VERSION 5.7 ;
  NOWIREEXTENSIONATPIN ON ;
  DIVIDERCHAR "/" ;
  BUSBITCHARS "[]" ;
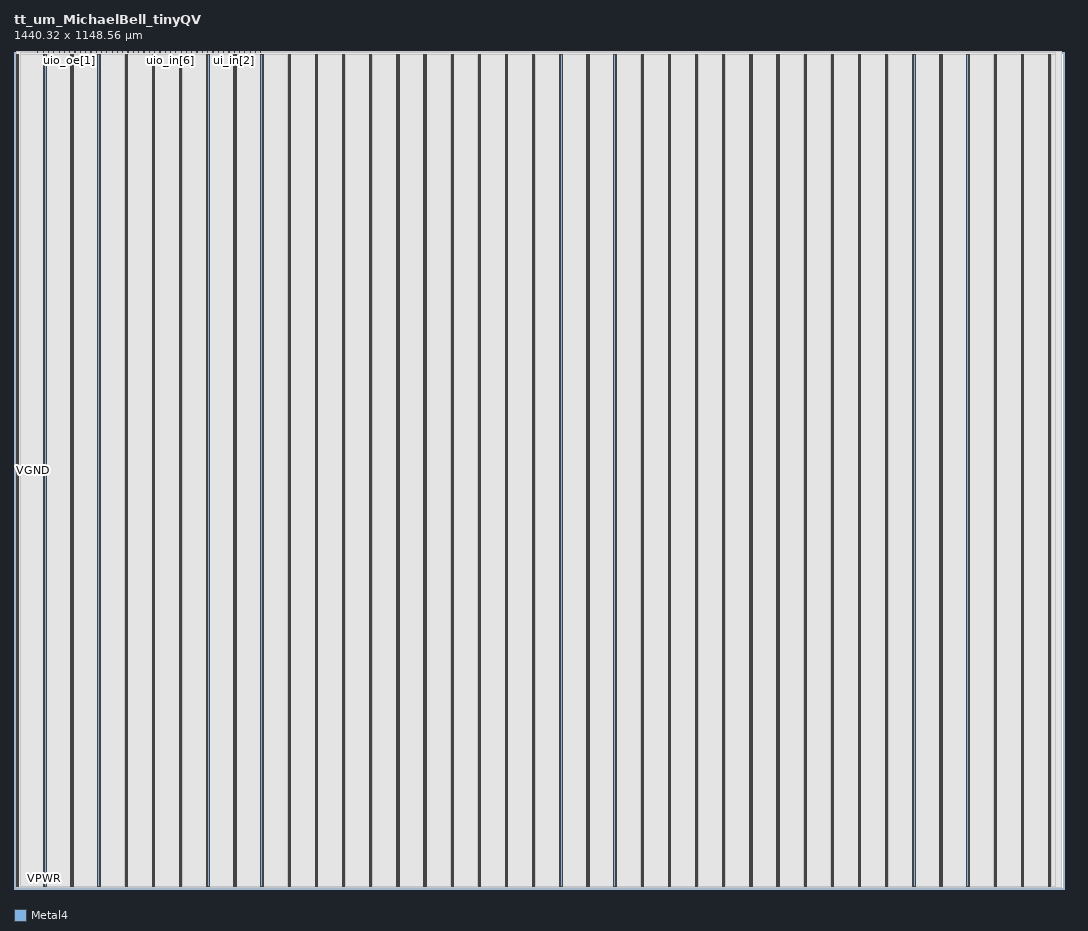
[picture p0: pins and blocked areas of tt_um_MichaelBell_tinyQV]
MACRO tt_um_MichaelBell_tinyQV
  CLASS BLOCK ;
  FOREIGN tt_um_MichaelBell_tinyQV ;
  ORIGIN 0.000 0.000 ;
  SIZE 1440.320 BY 1148.560 ;
  PIN VGND
    DIRECTION INOUT ;
    USE GROUND ;
    PORT
      LAYER Metal4 ;
        RECT 5.250 3.620 6.750 1144.940 ;
    END
    PORT
      LAYER Metal4 ;
        RECT 42.500 3.620 44.000 1144.940 ;
    END
    PORT
      LAYER Metal4 ;
        RECT 79.750 3.620 81.250 1144.940 ;
    END
    PORT
      LAYER Metal4 ;
        RECT 117.000 3.620 118.500 1144.940 ;
    END
    PORT
      LAYER Metal4 ;
        RECT 154.250 3.620 155.750 1144.940 ;
    END
    PORT
      LAYER Metal4 ;
        RECT 191.500 3.620 193.000 1144.940 ;
    END
    PORT
      LAYER Metal4 ;
        RECT 228.750 3.620 230.250 1144.940 ;
    END
    PORT
      LAYER Metal4 ;
        RECT 266.000 3.620 267.500 1144.940 ;
    END
    PORT
      LAYER Metal4 ;
        RECT 303.250 3.620 304.750 1144.940 ;
    END
    PORT
      LAYER Metal4 ;
        RECT 340.500 3.620 342.000 1144.940 ;
    END
    PORT
      LAYER Metal4 ;
        RECT 377.750 3.620 379.250 1144.940 ;
    END
    PORT
      LAYER Metal4 ;
        RECT 415.000 3.620 416.500 1144.940 ;
    END
    PORT
      LAYER Metal4 ;
        RECT 452.250 3.620 453.750 1144.940 ;
    END
    PORT
      LAYER Metal4 ;
        RECT 489.500 3.620 491.000 1144.940 ;
    END
    PORT
      LAYER Metal4 ;
        RECT 526.750 3.620 528.250 1144.940 ;
    END
    PORT
      LAYER Metal4 ;
        RECT 564.000 3.620 565.500 1144.940 ;
    END
    PORT
      LAYER Metal4 ;
        RECT 601.250 3.620 602.750 1144.940 ;
    END
    PORT
      LAYER Metal4 ;
        RECT 638.500 3.620 640.000 1144.940 ;
    END
    PORT
      LAYER Metal4 ;
        RECT 675.750 3.620 677.250 1144.940 ;
    END
    PORT
      LAYER Metal4 ;
        RECT 713.000 3.620 714.500 1144.940 ;
    END
    PORT
      LAYER Metal4 ;
        RECT 750.250 3.620 751.750 1144.940 ;
    END
    PORT
      LAYER Metal4 ;
        RECT 787.500 3.620 789.000 1144.940 ;
    END
    PORT
      LAYER Metal4 ;
        RECT 824.750 3.620 826.250 1144.940 ;
    END
    PORT
      LAYER Metal4 ;
        RECT 862.000 3.920 863.500 1144.640 ;
    END
    PORT
      LAYER Metal4 ;
        RECT 899.250 3.920 900.750 1144.640 ;
    END
    PORT
      LAYER Metal4 ;
        RECT 936.500 3.920 938.000 1144.640 ;
    END
    PORT
      LAYER Metal4 ;
        RECT 973.750 3.920 975.250 1144.640 ;
    END
    PORT
      LAYER Metal4 ;
        RECT 1011.000 3.920 1012.500 1144.640 ;
    END
    PORT
      LAYER Metal4 ;
        RECT 1048.250 3.920 1049.750 1144.640 ;
    END
    PORT
      LAYER Metal4 ;
        RECT 1085.500 3.920 1087.000 1144.640 ;
    END
    PORT
      LAYER Metal4 ;
        RECT 1122.750 3.920 1124.250 1144.640 ;
    END
    PORT
      LAYER Metal4 ;
        RECT 1160.000 3.920 1161.500 1144.640 ;
    END
    PORT
      LAYER Metal4 ;
        RECT 1197.250 3.920 1198.750 1144.640 ;
    END
    PORT
      LAYER Metal4 ;
        RECT 1234.500 3.920 1236.000 1144.640 ;
    END
    PORT
      LAYER Metal4 ;
        RECT 1271.750 3.920 1273.250 1144.640 ;
    END
    PORT
      LAYER Metal4 ;
        RECT 1309.000 3.920 1310.500 1144.640 ;
    END
    PORT
      LAYER Metal4 ;
        RECT 1346.250 3.920 1347.750 1144.640 ;
    END
    PORT
      LAYER Metal4 ;
        RECT 1383.500 3.920 1385.000 1144.640 ;
    END
    PORT
      LAYER Metal4 ;
        RECT 1420.750 3.920 1422.250 1144.640 ;
    END
  END VGND
  PIN VPWR
    DIRECTION INOUT ;
    USE POWER ;
    PORT
      LAYER Metal4 ;
        RECT 3.470 3.620 4.970 1144.940 ;
    END
    PORT
      LAYER Metal4 ;
        RECT 40.720 3.620 42.220 1144.940 ;
    END
    PORT
      LAYER Metal4 ;
        RECT 77.970 3.620 79.470 1144.940 ;
    END
    PORT
      LAYER Metal4 ;
        RECT 115.220 3.620 116.720 1144.940 ;
    END
    PORT
      LAYER Metal4 ;
        RECT 152.470 3.620 153.970 1144.940 ;
    END
    PORT
      LAYER Metal4 ;
        RECT 189.720 3.620 191.220 1144.940 ;
    END
    PORT
      LAYER Metal4 ;
        RECT 226.970 3.620 228.470 1144.940 ;
    END
    PORT
      LAYER Metal4 ;
        RECT 264.220 3.620 265.720 1144.940 ;
    END
    PORT
      LAYER Metal4 ;
        RECT 301.470 3.620 302.970 1144.940 ;
    END
    PORT
      LAYER Metal4 ;
        RECT 338.720 3.620 340.220 1144.940 ;
    END
    PORT
      LAYER Metal4 ;
        RECT 375.970 3.620 377.470 1144.940 ;
    END
    PORT
      LAYER Metal4 ;
        RECT 413.220 3.620 414.720 1144.940 ;
    END
    PORT
      LAYER Metal4 ;
        RECT 450.470 3.620 451.970 1144.940 ;
    END
    PORT
      LAYER Metal4 ;
        RECT 487.720 3.620 489.220 1144.940 ;
    END
    PORT
      LAYER Metal4 ;
        RECT 524.970 3.620 526.470 1144.940 ;
    END
    PORT
      LAYER Metal4 ;
        RECT 562.220 3.620 563.720 1144.940 ;
    END
    PORT
      LAYER Metal4 ;
        RECT 599.470 3.620 600.970 1144.940 ;
    END
    PORT
      LAYER Metal4 ;
        RECT 636.720 3.620 638.220 1144.940 ;
    END
    PORT
      LAYER Metal4 ;
        RECT 673.970 3.620 675.470 1144.940 ;
    END
    PORT
      LAYER Metal4 ;
        RECT 711.220 3.620 712.720 1144.940 ;
    END
    PORT
      LAYER Metal4 ;
        RECT 748.470 3.620 749.970 1144.940 ;
    END
    PORT
      LAYER Metal4 ;
        RECT 785.720 3.620 787.220 1144.940 ;
    END
    PORT
      LAYER Metal4 ;
        RECT 822.970 3.620 824.470 1144.940 ;
    END
    PORT
      LAYER Metal4 ;
        RECT 860.220 3.920 861.720 1144.640 ;
    END
    PORT
      LAYER Metal4 ;
        RECT 897.470 3.920 898.970 1144.640 ;
    END
    PORT
      LAYER Metal4 ;
        RECT 934.720 3.920 936.220 1144.640 ;
    END
    PORT
      LAYER Metal4 ;
        RECT 971.970 3.920 973.470 1144.640 ;
    END
    PORT
      LAYER Metal4 ;
        RECT 1009.220 3.920 1010.720 1144.640 ;
    END
    PORT
      LAYER Metal4 ;
        RECT 1046.470 3.920 1047.970 1144.640 ;
    END
    PORT
      LAYER Metal4 ;
        RECT 1083.720 3.920 1085.220 1144.640 ;
    END
    PORT
      LAYER Metal4 ;
        RECT 1120.970 3.920 1122.470 1144.640 ;
    END
    PORT
      LAYER Metal4 ;
        RECT 1158.220 3.920 1159.720 1144.640 ;
    END
    PORT
      LAYER Metal4 ;
        RECT 1195.470 3.920 1196.970 1144.640 ;
    END
    PORT
      LAYER Metal4 ;
        RECT 1232.720 3.920 1234.220 1144.640 ;
    END
    PORT
      LAYER Metal4 ;
        RECT 1269.970 3.920 1271.470 1144.640 ;
    END
    PORT
      LAYER Metal4 ;
        RECT 1307.220 3.920 1308.720 1144.640 ;
    END
    PORT
      LAYER Metal4 ;
        RECT 1344.470 3.920 1345.970 1144.640 ;
    END
    PORT
      LAYER Metal4 ;
        RECT 1381.720 3.920 1383.220 1144.640 ;
    END
    PORT
      LAYER Metal4 ;
        RECT 1418.970 3.920 1420.470 1144.640 ;
    END
  END VPWR
  PIN clk
    DIRECTION INPUT ;
    USE SIGNAL ;
    ANTENNAGATEAREA 9.476000 ;
    PORT
      LAYER Metal4 ;
        RECT 331.090 1147.560 331.390 1148.560 ;
    END
  END clk
  PIN ena
    DIRECTION INPUT ;
    USE SIGNAL ;
    PORT
      LAYER Metal4 ;
        RECT 338.370 1147.560 338.670 1148.560 ;
    END
  END ena
  PIN rst_n
    DIRECTION INPUT ;
    USE SIGNAL ;
    ANTENNAGATEAREA 1.102000 ;
    PORT
      LAYER Metal4 ;
        RECT 323.810 1147.560 324.110 1148.560 ;
    END
  END rst_n
  PIN ui_in[0]
    DIRECTION INPUT ;
    USE SIGNAL ;
    ANTENNAGATEAREA 0.396000 ;
    PORT
      LAYER Metal4 ;
        RECT 316.530 1147.560 316.830 1148.560 ;
    END
  END ui_in[0]
  PIN ui_in[1]
    DIRECTION INPUT ;
    USE SIGNAL ;
    ANTENNAGATEAREA 1.102000 ;
    PORT
      LAYER Metal4 ;
        RECT 309.250 1147.560 309.550 1148.560 ;
    END
  END ui_in[1]
  PIN ui_in[2]
    DIRECTION INPUT ;
    USE SIGNAL ;
    ANTENNAGATEAREA 0.396000 ;
    PORT
      LAYER Metal4 ;
        RECT 301.970 1147.560 302.270 1148.560 ;
    END
  END ui_in[2]
  PIN ui_in[3]
    DIRECTION INPUT ;
    USE SIGNAL ;
    ANTENNAGATEAREA 0.396000 ;
    PORT
      LAYER Metal4 ;
        RECT 294.690 1147.560 294.990 1148.560 ;
    END
  END ui_in[3]
  PIN ui_in[4]
    DIRECTION INPUT ;
    USE SIGNAL ;
    ANTENNAGATEAREA 0.396000 ;
    PORT
      LAYER Metal4 ;
        RECT 287.410 1147.560 287.710 1148.560 ;
    END
  END ui_in[4]
  PIN ui_in[5]
    DIRECTION INPUT ;
    USE SIGNAL ;
    ANTENNAGATEAREA 0.396000 ;
    PORT
      LAYER Metal4 ;
        RECT 280.130 1147.560 280.430 1148.560 ;
    END
  END ui_in[5]
  PIN ui_in[6]
    DIRECTION INPUT ;
    USE SIGNAL ;
    ANTENNAGATEAREA 0.396000 ;
    PORT
      LAYER Metal4 ;
        RECT 272.850 1147.560 273.150 1148.560 ;
    END
  END ui_in[6]
  PIN ui_in[7]
    DIRECTION INPUT ;
    USE SIGNAL ;
    ANTENNAGATEAREA 0.396000 ;
    PORT
      LAYER Metal4 ;
        RECT 265.570 1147.560 265.870 1148.560 ;
    END
  END ui_in[7]
  PIN uio_in[0]
    DIRECTION INPUT ;
    USE SIGNAL ;
    PORT
      LAYER Metal4 ;
        RECT 258.290 1147.560 258.590 1148.560 ;
    END
  END uio_in[0]
  PIN uio_in[1]
    DIRECTION INPUT ;
    USE SIGNAL ;
    ANTENNAGATEAREA 1.102000 ;
    PORT
      LAYER Metal4 ;
        RECT 251.010 1147.560 251.310 1148.560 ;
    END
  END uio_in[1]
  PIN uio_in[2]
    DIRECTION INPUT ;
    USE SIGNAL ;
    ANTENNAGATEAREA 1.102000 ;
    PORT
      LAYER Metal4 ;
        RECT 243.730 1147.560 244.030 1148.560 ;
    END
  END uio_in[2]
  PIN uio_in[3]
    DIRECTION INPUT ;
    USE SIGNAL ;
    PORT
      LAYER Metal4 ;
        RECT 236.450 1147.560 236.750 1148.560 ;
    END
  END uio_in[3]
  PIN uio_in[4]
    DIRECTION INPUT ;
    USE SIGNAL ;
    ANTENNAGATEAREA 1.102000 ;
    PORT
      LAYER Metal4 ;
        RECT 229.170 1147.560 229.470 1148.560 ;
    END
  END uio_in[4]
  PIN uio_in[5]
    DIRECTION INPUT ;
    USE SIGNAL ;
    ANTENNAGATEAREA 1.102000 ;
    PORT
      LAYER Metal4 ;
        RECT 221.890 1147.560 222.190 1148.560 ;
    END
  END uio_in[5]
  PIN uio_in[6]
    DIRECTION INPUT ;
    USE SIGNAL ;
    PORT
      LAYER Metal4 ;
        RECT 214.610 1147.560 214.910 1148.560 ;
    END
  END uio_in[6]
  PIN uio_in[7]
    DIRECTION INPUT ;
    USE SIGNAL ;
    PORT
      LAYER Metal4 ;
        RECT 207.330 1147.560 207.630 1148.560 ;
    END
  END uio_in[7]
  PIN uio_oe[0]
    DIRECTION OUTPUT ;
    USE SIGNAL ;
    ANTENNADIFFAREA 1.182800 ;
    PORT
      LAYER Metal4 ;
        RECT 83.570 1147.560 83.870 1148.560 ;
    END
  END uio_oe[0]
  PIN uio_oe[1]
    DIRECTION OUTPUT ;
    USE SIGNAL ;
    ANTENNADIFFAREA 4.731200 ;
    PORT
      LAYER Metal4 ;
        RECT 76.290 1147.560 76.590 1148.560 ;
    END
  END uio_oe[1]
  PIN uio_oe[2]
    DIRECTION OUTPUT ;
    USE SIGNAL ;
    ANTENNAGATEAREA 0.741000 ;
    ANTENNADIFFAREA 4.731200 ;
    PORT
      LAYER Metal4 ;
        RECT 69.010 1147.560 69.310 1148.560 ;
    END
  END uio_oe[2]
  PIN uio_oe[3]
    DIRECTION OUTPUT ;
    USE SIGNAL ;
    ANTENNADIFFAREA 1.182800 ;
    PORT
      LAYER Metal4 ;
        RECT 61.730 1147.560 62.030 1148.560 ;
    END
  END uio_oe[3]
  PIN uio_oe[4]
    DIRECTION OUTPUT ;
    USE SIGNAL ;
    ANTENNADIFFAREA 1.182800 ;
    PORT
      LAYER Metal4 ;
        RECT 54.450 1147.560 54.750 1148.560 ;
    END
  END uio_oe[4]
  PIN uio_oe[5]
    DIRECTION OUTPUT ;
    USE SIGNAL ;
    ANTENNADIFFAREA 1.182800 ;
    PORT
      LAYER Metal4 ;
        RECT 47.170 1147.560 47.470 1148.560 ;
    END
  END uio_oe[5]
  PIN uio_oe[6]
    DIRECTION OUTPUT ;
    USE SIGNAL ;
    ANTENNADIFFAREA 1.182800 ;
    PORT
      LAYER Metal4 ;
        RECT 39.890 1147.560 40.190 1148.560 ;
    END
  END uio_oe[6]
  PIN uio_oe[7]
    DIRECTION OUTPUT ;
    USE SIGNAL ;
    ANTENNADIFFAREA 1.182800 ;
    PORT
      LAYER Metal4 ;
        RECT 32.610 1147.560 32.910 1148.560 ;
    END
  END uio_oe[7]
  PIN uio_out[0]
    DIRECTION OUTPUT ;
    USE SIGNAL ;
    ANTENNADIFFAREA 1.182800 ;
    PORT
      LAYER Metal4 ;
        RECT 141.810 1147.560 142.110 1148.560 ;
    END
  END uio_out[0]
  PIN uio_out[1]
    DIRECTION OUTPUT ;
    USE SIGNAL ;
    ANTENNADIFFAREA 4.024000 ;
    PORT
      LAYER Metal4 ;
        RECT 134.530 1147.560 134.830 1148.560 ;
    END
  END uio_out[1]
  PIN uio_out[2]
    DIRECTION OUTPUT ;
    USE SIGNAL ;
    ANTENNADIFFAREA 2.609600 ;
    PORT
      LAYER Metal4 ;
        RECT 127.250 1147.560 127.550 1148.560 ;
    END
  END uio_out[2]
  PIN uio_out[3]
    DIRECTION OUTPUT ;
    USE SIGNAL ;
    ANTENNADIFFAREA 7.096800 ;
    PORT
      LAYER Metal4 ;
        RECT 119.970 1147.560 120.270 1148.560 ;
    END
  END uio_out[3]
  PIN uio_out[4]
    DIRECTION OUTPUT ;
    USE SIGNAL ;
    ANTENNADIFFAREA 2.609600 ;
    PORT
      LAYER Metal4 ;
        RECT 112.690 1147.560 112.990 1148.560 ;
    END
  END uio_out[4]
  PIN uio_out[5]
    DIRECTION OUTPUT ;
    USE SIGNAL ;
    ANTENNADIFFAREA 4.731200 ;
    PORT
      LAYER Metal4 ;
        RECT 105.410 1147.560 105.710 1148.560 ;
    END
  END uio_out[5]
  PIN uio_out[6]
    DIRECTION OUTPUT ;
    USE SIGNAL ;
    ANTENNADIFFAREA 4.731200 ;
    PORT
      LAYER Metal4 ;
        RECT 98.130 1147.560 98.430 1148.560 ;
    END
  END uio_out[6]
  PIN uio_out[7]
    DIRECTION OUTPUT ;
    USE SIGNAL ;
    ANTENNADIFFAREA 1.182800 ;
    PORT
      LAYER Metal4 ;
        RECT 90.850 1147.560 91.150 1148.560 ;
    END
  END uio_out[7]
  PIN uo_out[0]
    DIRECTION OUTPUT ;
    USE SIGNAL ;
    ANTENNADIFFAREA 2.365600 ;
    PORT
      LAYER Metal4 ;
        RECT 200.050 1147.560 200.350 1148.560 ;
    END
  END uo_out[0]
  PIN uo_out[1]
    DIRECTION OUTPUT ;
    USE SIGNAL ;
    ANTENNADIFFAREA 2.365600 ;
    PORT
      LAYER Metal4 ;
        RECT 192.770 1147.560 193.070 1148.560 ;
    END
  END uo_out[1]
  PIN uo_out[2]
    DIRECTION OUTPUT ;
    USE SIGNAL ;
    ANTENNADIFFAREA 1.182800 ;
    PORT
      LAYER Metal4 ;
        RECT 185.490 1147.560 185.790 1148.560 ;
    END
  END uo_out[2]
  PIN uo_out[3]
    DIRECTION OUTPUT ;
    USE SIGNAL ;
    ANTENNADIFFAREA 3.879200 ;
    PORT
      LAYER Metal4 ;
        RECT 178.210 1147.560 178.510 1148.560 ;
    END
  END uo_out[3]
  PIN uo_out[4]
    DIRECTION OUTPUT ;
    USE SIGNAL ;
    ANTENNADIFFAREA 4.030500 ;
    PORT
      LAYER Metal4 ;
        RECT 170.930 1147.560 171.230 1148.560 ;
    END
  END uo_out[4]
  PIN uo_out[5]
    DIRECTION OUTPUT ;
    USE SIGNAL ;
    ANTENNADIFFAREA 4.408000 ;
    PORT
      LAYER Metal4 ;
        RECT 163.650 1147.560 163.950 1148.560 ;
    END
  END uo_out[5]
  PIN uo_out[6]
    DIRECTION OUTPUT ;
    USE SIGNAL ;
    ANTENNADIFFAREA 2.365600 ;
    PORT
      LAYER Metal4 ;
        RECT 156.370 1147.560 156.670 1148.560 ;
    END
  END uo_out[6]
  PIN uo_out[7]
    DIRECTION OUTPUT ;
    USE SIGNAL ;
    ANTENNADIFFAREA 4.731200 ;
    PORT
      LAYER Metal4 ;
        RECT 149.090 1147.560 149.390 1148.560 ;
    END
  END uo_out[7]
  OBS
      LAYER Nwell ;
        RECT 2.930 1142.480 1437.390 1145.070 ;
      LAYER Pwell ;
        RECT 2.930 1138.960 849.390 1142.480 ;
      LAYER Nwell ;
        RECT 849.390 1138.960 1437.390 1142.480 ;
        RECT 2.930 1134.640 1437.390 1138.960 ;
      LAYER Pwell ;
        RECT 2.930 1131.120 849.390 1134.640 ;
      LAYER Nwell ;
        RECT 849.390 1131.120 1437.390 1134.640 ;
        RECT 2.930 1126.800 1437.390 1131.120 ;
      LAYER Pwell ;
        RECT 2.930 1123.280 849.390 1126.800 ;
      LAYER Nwell ;
        RECT 849.390 1123.280 1437.390 1126.800 ;
        RECT 2.930 1118.960 1437.390 1123.280 ;
      LAYER Pwell ;
        RECT 2.930 1115.440 849.390 1118.960 ;
      LAYER Nwell ;
        RECT 849.390 1115.440 1437.390 1118.960 ;
        RECT 2.930 1111.120 1437.390 1115.440 ;
      LAYER Pwell ;
        RECT 2.930 1107.600 849.390 1111.120 ;
      LAYER Nwell ;
        RECT 849.390 1107.600 1437.390 1111.120 ;
        RECT 2.930 1103.280 1437.390 1107.600 ;
      LAYER Pwell ;
        RECT 2.930 1099.760 849.390 1103.280 ;
      LAYER Nwell ;
        RECT 849.390 1099.760 1437.390 1103.280 ;
        RECT 2.930 1095.440 1437.390 1099.760 ;
      LAYER Pwell ;
        RECT 2.930 1091.920 849.390 1095.440 ;
      LAYER Nwell ;
        RECT 849.390 1091.920 1437.390 1095.440 ;
        RECT 2.930 1087.600 1437.390 1091.920 ;
      LAYER Pwell ;
        RECT 2.930 1084.080 1437.390 1087.600 ;
      LAYER Nwell ;
        RECT 2.930 1079.760 1437.390 1084.080 ;
      LAYER Pwell ;
        RECT 2.930 1076.240 1437.390 1079.760 ;
      LAYER Nwell ;
        RECT 2.930 1071.920 1437.390 1076.240 ;
      LAYER Pwell ;
        RECT 2.930 1068.400 1437.390 1071.920 ;
      LAYER Nwell ;
        RECT 2.930 1064.080 1437.390 1068.400 ;
      LAYER Pwell ;
        RECT 2.930 1060.560 1437.390 1064.080 ;
      LAYER Nwell ;
        RECT 2.930 1056.240 1437.390 1060.560 ;
      LAYER Pwell ;
        RECT 2.930 1052.720 1437.390 1056.240 ;
      LAYER Nwell ;
        RECT 2.930 1048.400 1437.390 1052.720 ;
      LAYER Pwell ;
        RECT 2.930 1044.880 1437.390 1048.400 ;
      LAYER Nwell ;
        RECT 2.930 1040.560 1437.390 1044.880 ;
      LAYER Pwell ;
        RECT 2.930 1037.040 1437.390 1040.560 ;
      LAYER Nwell ;
        RECT 2.930 1032.720 1437.390 1037.040 ;
      LAYER Pwell ;
        RECT 2.930 1029.200 1437.390 1032.720 ;
      LAYER Nwell ;
        RECT 2.930 1024.880 1437.390 1029.200 ;
      LAYER Pwell ;
        RECT 2.930 1021.360 1437.390 1024.880 ;
      LAYER Nwell ;
        RECT 2.930 1017.040 1437.390 1021.360 ;
      LAYER Pwell ;
        RECT 2.930 1013.520 1437.390 1017.040 ;
      LAYER Nwell ;
        RECT 2.930 1009.200 1437.390 1013.520 ;
      LAYER Pwell ;
        RECT 2.930 1005.680 1437.390 1009.200 ;
      LAYER Nwell ;
        RECT 2.930 1001.360 1437.390 1005.680 ;
      LAYER Pwell ;
        RECT 2.930 997.840 1437.390 1001.360 ;
      LAYER Nwell ;
        RECT 2.930 993.520 1437.390 997.840 ;
      LAYER Pwell ;
        RECT 2.930 990.000 1437.390 993.520 ;
      LAYER Nwell ;
        RECT 2.930 985.680 1437.390 990.000 ;
      LAYER Pwell ;
        RECT 2.930 982.160 1437.390 985.680 ;
      LAYER Nwell ;
        RECT 2.930 977.840 1437.390 982.160 ;
      LAYER Pwell ;
        RECT 2.930 974.320 1437.390 977.840 ;
      LAYER Nwell ;
        RECT 2.930 970.000 1437.390 974.320 ;
      LAYER Pwell ;
        RECT 2.930 966.480 1437.390 970.000 ;
      LAYER Nwell ;
        RECT 2.930 962.160 1437.390 966.480 ;
      LAYER Pwell ;
        RECT 2.930 958.640 1437.390 962.160 ;
      LAYER Nwell ;
        RECT 2.930 954.320 1437.390 958.640 ;
      LAYER Pwell ;
        RECT 2.930 950.800 1437.390 954.320 ;
      LAYER Nwell ;
        RECT 2.930 946.480 1437.390 950.800 ;
      LAYER Pwell ;
        RECT 2.930 942.960 1437.390 946.480 ;
      LAYER Nwell ;
        RECT 2.930 938.640 1437.390 942.960 ;
      LAYER Pwell ;
        RECT 2.930 935.120 1437.390 938.640 ;
      LAYER Nwell ;
        RECT 2.930 930.800 1437.390 935.120 ;
      LAYER Pwell ;
        RECT 2.930 927.280 1437.390 930.800 ;
      LAYER Nwell ;
        RECT 2.930 922.960 1437.390 927.280 ;
      LAYER Pwell ;
        RECT 2.930 919.440 1437.390 922.960 ;
      LAYER Nwell ;
        RECT 2.930 915.120 1437.390 919.440 ;
      LAYER Pwell ;
        RECT 2.930 911.600 1437.390 915.120 ;
      LAYER Nwell ;
        RECT 2.930 907.280 1437.390 911.600 ;
      LAYER Pwell ;
        RECT 2.930 903.760 1437.390 907.280 ;
      LAYER Nwell ;
        RECT 2.930 899.440 1437.390 903.760 ;
      LAYER Pwell ;
        RECT 2.930 895.920 1437.390 899.440 ;
      LAYER Nwell ;
        RECT 2.930 891.600 1437.390 895.920 ;
      LAYER Pwell ;
        RECT 2.930 888.080 1437.390 891.600 ;
      LAYER Nwell ;
        RECT 2.930 883.760 1437.390 888.080 ;
      LAYER Pwell ;
        RECT 2.930 880.240 1437.390 883.760 ;
      LAYER Nwell ;
        RECT 2.930 875.920 1437.390 880.240 ;
      LAYER Pwell ;
        RECT 2.930 872.400 1437.390 875.920 ;
      LAYER Nwell ;
        RECT 2.930 868.080 1437.390 872.400 ;
      LAYER Pwell ;
        RECT 2.930 864.560 1437.390 868.080 ;
      LAYER Nwell ;
        RECT 2.930 860.240 1437.390 864.560 ;
      LAYER Pwell ;
        RECT 2.930 856.720 1437.390 860.240 ;
      LAYER Nwell ;
        RECT 2.930 852.400 1437.390 856.720 ;
      LAYER Pwell ;
        RECT 2.930 848.880 1437.390 852.400 ;
      LAYER Nwell ;
        RECT 2.930 844.560 1437.390 848.880 ;
      LAYER Pwell ;
        RECT 2.930 841.040 1437.390 844.560 ;
      LAYER Nwell ;
        RECT 2.930 836.720 1437.390 841.040 ;
      LAYER Pwell ;
        RECT 2.930 833.200 1437.390 836.720 ;
      LAYER Nwell ;
        RECT 2.930 828.880 1437.390 833.200 ;
      LAYER Pwell ;
        RECT 2.930 825.360 1437.390 828.880 ;
      LAYER Nwell ;
        RECT 2.930 821.040 1437.390 825.360 ;
      LAYER Pwell ;
        RECT 2.930 817.520 1437.390 821.040 ;
      LAYER Nwell ;
        RECT 2.930 813.200 1437.390 817.520 ;
      LAYER Pwell ;
        RECT 2.930 809.680 1437.390 813.200 ;
      LAYER Nwell ;
        RECT 2.930 805.360 1437.390 809.680 ;
      LAYER Pwell ;
        RECT 2.930 801.840 1437.390 805.360 ;
      LAYER Nwell ;
        RECT 2.930 797.520 1437.390 801.840 ;
      LAYER Pwell ;
        RECT 2.930 794.000 1437.390 797.520 ;
      LAYER Nwell ;
        RECT 2.930 789.680 1437.390 794.000 ;
      LAYER Pwell ;
        RECT 2.930 786.160 1437.390 789.680 ;
      LAYER Nwell ;
        RECT 2.930 781.840 1437.390 786.160 ;
      LAYER Pwell ;
        RECT 2.930 778.320 1437.390 781.840 ;
      LAYER Nwell ;
        RECT 2.930 774.000 1437.390 778.320 ;
      LAYER Pwell ;
        RECT 2.930 770.480 1437.390 774.000 ;
      LAYER Nwell ;
        RECT 2.930 766.160 1437.390 770.480 ;
      LAYER Pwell ;
        RECT 2.930 762.640 1437.390 766.160 ;
      LAYER Nwell ;
        RECT 2.930 758.320 1437.390 762.640 ;
      LAYER Pwell ;
        RECT 2.930 754.800 1437.390 758.320 ;
      LAYER Nwell ;
        RECT 2.930 750.480 1437.390 754.800 ;
      LAYER Pwell ;
        RECT 2.930 746.960 1437.390 750.480 ;
      LAYER Nwell ;
        RECT 2.930 742.640 1437.390 746.960 ;
      LAYER Pwell ;
        RECT 2.930 739.120 1437.390 742.640 ;
      LAYER Nwell ;
        RECT 2.930 734.800 1437.390 739.120 ;
      LAYER Pwell ;
        RECT 2.930 731.280 1437.390 734.800 ;
      LAYER Nwell ;
        RECT 2.930 726.960 1437.390 731.280 ;
      LAYER Pwell ;
        RECT 2.930 723.440 1437.390 726.960 ;
      LAYER Nwell ;
        RECT 2.930 719.120 1437.390 723.440 ;
      LAYER Pwell ;
        RECT 2.930 715.600 1437.390 719.120 ;
      LAYER Nwell ;
        RECT 2.930 711.280 1437.390 715.600 ;
      LAYER Pwell ;
        RECT 2.930 707.760 1437.390 711.280 ;
      LAYER Nwell ;
        RECT 2.930 703.440 1437.390 707.760 ;
      LAYER Pwell ;
        RECT 2.930 699.920 1437.390 703.440 ;
      LAYER Nwell ;
        RECT 2.930 695.600 1437.390 699.920 ;
      LAYER Pwell ;
        RECT 2.930 692.080 1437.390 695.600 ;
      LAYER Nwell ;
        RECT 2.930 687.760 1437.390 692.080 ;
      LAYER Pwell ;
        RECT 2.930 684.240 1437.390 687.760 ;
      LAYER Nwell ;
        RECT 2.930 679.920 1437.390 684.240 ;
      LAYER Pwell ;
        RECT 2.930 676.400 1437.390 679.920 ;
      LAYER Nwell ;
        RECT 2.930 672.080 1437.390 676.400 ;
      LAYER Pwell ;
        RECT 2.930 668.560 1437.390 672.080 ;
      LAYER Nwell ;
        RECT 2.930 664.240 1437.390 668.560 ;
      LAYER Pwell ;
        RECT 2.930 660.720 1437.390 664.240 ;
      LAYER Nwell ;
        RECT 2.930 656.400 1437.390 660.720 ;
      LAYER Pwell ;
        RECT 2.930 652.880 1437.390 656.400 ;
      LAYER Nwell ;
        RECT 2.930 648.560 1437.390 652.880 ;
      LAYER Pwell ;
        RECT 2.930 645.040 1437.390 648.560 ;
      LAYER Nwell ;
        RECT 2.930 640.720 1437.390 645.040 ;
      LAYER Pwell ;
        RECT 2.930 637.200 1437.390 640.720 ;
      LAYER Nwell ;
        RECT 2.930 632.880 1437.390 637.200 ;
      LAYER Pwell ;
        RECT 2.930 629.360 1437.390 632.880 ;
      LAYER Nwell ;
        RECT 2.930 625.040 1437.390 629.360 ;
      LAYER Pwell ;
        RECT 2.930 621.520 1437.390 625.040 ;
      LAYER Nwell ;
        RECT 2.930 617.200 1437.390 621.520 ;
      LAYER Pwell ;
        RECT 2.930 613.680 1437.390 617.200 ;
      LAYER Nwell ;
        RECT 2.930 609.360 1437.390 613.680 ;
      LAYER Pwell ;
        RECT 2.930 605.840 1437.390 609.360 ;
      LAYER Nwell ;
        RECT 2.930 601.520 1437.390 605.840 ;
      LAYER Pwell ;
        RECT 2.930 598.000 1437.390 601.520 ;
      LAYER Nwell ;
        RECT 2.930 593.680 1437.390 598.000 ;
      LAYER Pwell ;
        RECT 2.930 590.160 1437.390 593.680 ;
      LAYER Nwell ;
        RECT 2.930 585.840 1437.390 590.160 ;
      LAYER Pwell ;
        RECT 2.930 582.320 1437.390 585.840 ;
      LAYER Nwell ;
        RECT 2.930 578.000 1437.390 582.320 ;
      LAYER Pwell ;
        RECT 2.930 574.480 1437.390 578.000 ;
      LAYER Nwell ;
        RECT 2.930 570.160 1437.390 574.480 ;
      LAYER Pwell ;
        RECT 2.930 566.640 1437.390 570.160 ;
      LAYER Nwell ;
        RECT 2.930 562.320 1437.390 566.640 ;
      LAYER Pwell ;
        RECT 2.930 558.800 1437.390 562.320 ;
      LAYER Nwell ;
        RECT 2.930 554.480 1437.390 558.800 ;
      LAYER Pwell ;
        RECT 2.930 550.960 1437.390 554.480 ;
      LAYER Nwell ;
        RECT 2.930 546.640 1437.390 550.960 ;
      LAYER Pwell ;
        RECT 2.930 543.120 1437.390 546.640 ;
      LAYER Nwell ;
        RECT 2.930 538.800 1437.390 543.120 ;
      LAYER Pwell ;
        RECT 2.930 535.280 1437.390 538.800 ;
      LAYER Nwell ;
        RECT 2.930 530.960 1437.390 535.280 ;
      LAYER Pwell ;
        RECT 2.930 527.440 1437.390 530.960 ;
      LAYER Nwell ;
        RECT 2.930 523.120 1437.390 527.440 ;
      LAYER Pwell ;
        RECT 2.930 519.600 1437.390 523.120 ;
      LAYER Nwell ;
        RECT 2.930 515.280 1437.390 519.600 ;
      LAYER Pwell ;
        RECT 2.930 511.760 1437.390 515.280 ;
      LAYER Nwell ;
        RECT 2.930 507.440 1437.390 511.760 ;
      LAYER Pwell ;
        RECT 2.930 503.920 1437.390 507.440 ;
      LAYER Nwell ;
        RECT 2.930 499.600 1437.390 503.920 ;
      LAYER Pwell ;
        RECT 2.930 496.080 1437.390 499.600 ;
      LAYER Nwell ;
        RECT 2.930 491.760 1437.390 496.080 ;
      LAYER Pwell ;
        RECT 2.930 488.240 1437.390 491.760 ;
      LAYER Nwell ;
        RECT 2.930 483.920 1437.390 488.240 ;
      LAYER Pwell ;
        RECT 2.930 480.400 1437.390 483.920 ;
      LAYER Nwell ;
        RECT 2.930 476.080 1437.390 480.400 ;
      LAYER Pwell ;
        RECT 2.930 472.560 1437.390 476.080 ;
      LAYER Nwell ;
        RECT 2.930 468.240 1437.390 472.560 ;
      LAYER Pwell ;
        RECT 2.930 464.720 1437.390 468.240 ;
      LAYER Nwell ;
        RECT 2.930 460.400 1437.390 464.720 ;
      LAYER Pwell ;
        RECT 2.930 456.880 1437.390 460.400 ;
      LAYER Nwell ;
        RECT 2.930 452.560 1437.390 456.880 ;
      LAYER Pwell ;
        RECT 2.930 449.040 1437.390 452.560 ;
      LAYER Nwell ;
        RECT 2.930 444.720 1437.390 449.040 ;
      LAYER Pwell ;
        RECT 2.930 441.200 1437.390 444.720 ;
      LAYER Nwell ;
        RECT 2.930 436.880 1437.390 441.200 ;
      LAYER Pwell ;
        RECT 2.930 433.360 1437.390 436.880 ;
      LAYER Nwell ;
        RECT 2.930 429.040 1437.390 433.360 ;
      LAYER Pwell ;
        RECT 2.930 425.520 1437.390 429.040 ;
      LAYER Nwell ;
        RECT 2.930 421.200 1437.390 425.520 ;
      LAYER Pwell ;
        RECT 2.930 417.680 1437.390 421.200 ;
      LAYER Nwell ;
        RECT 2.930 413.360 1437.390 417.680 ;
      LAYER Pwell ;
        RECT 2.930 409.840 1437.390 413.360 ;
      LAYER Nwell ;
        RECT 2.930 405.520 1437.390 409.840 ;
      LAYER Pwell ;
        RECT 2.930 402.000 1437.390 405.520 ;
      LAYER Nwell ;
        RECT 2.930 397.680 1437.390 402.000 ;
      LAYER Pwell ;
        RECT 2.930 394.160 1437.390 397.680 ;
      LAYER Nwell ;
        RECT 2.930 389.840 1437.390 394.160 ;
      LAYER Pwell ;
        RECT 2.930 386.320 1437.390 389.840 ;
      LAYER Nwell ;
        RECT 2.930 382.000 1437.390 386.320 ;
      LAYER Pwell ;
        RECT 2.930 378.480 1437.390 382.000 ;
      LAYER Nwell ;
        RECT 2.930 374.160 1437.390 378.480 ;
      LAYER Pwell ;
        RECT 2.930 370.640 1437.390 374.160 ;
      LAYER Nwell ;
        RECT 2.930 366.320 1437.390 370.640 ;
      LAYER Pwell ;
        RECT 2.930 362.800 1437.390 366.320 ;
      LAYER Nwell ;
        RECT 2.930 358.480 1437.390 362.800 ;
      LAYER Pwell ;
        RECT 2.930 354.960 1437.390 358.480 ;
      LAYER Nwell ;
        RECT 2.930 350.640 1437.390 354.960 ;
      LAYER Pwell ;
        RECT 2.930 347.120 1437.390 350.640 ;
      LAYER Nwell ;
        RECT 2.930 342.800 1437.390 347.120 ;
      LAYER Pwell ;
        RECT 2.930 339.280 1437.390 342.800 ;
      LAYER Nwell ;
        RECT 2.930 334.960 1437.390 339.280 ;
      LAYER Pwell ;
        RECT 2.930 331.440 1437.390 334.960 ;
      LAYER Nwell ;
        RECT 2.930 327.120 1437.390 331.440 ;
      LAYER Pwell ;
        RECT 2.930 323.600 1437.390 327.120 ;
      LAYER Nwell ;
        RECT 2.930 319.280 1437.390 323.600 ;
      LAYER Pwell ;
        RECT 2.930 315.760 1437.390 319.280 ;
      LAYER Nwell ;
        RECT 2.930 311.440 1437.390 315.760 ;
      LAYER Pwell ;
        RECT 2.930 307.920 1437.390 311.440 ;
      LAYER Nwell ;
        RECT 2.930 303.600 1437.390 307.920 ;
      LAYER Pwell ;
        RECT 2.930 300.080 1437.390 303.600 ;
      LAYER Nwell ;
        RECT 2.930 295.760 1437.390 300.080 ;
      LAYER Pwell ;
        RECT 2.930 292.240 1437.390 295.760 ;
      LAYER Nwell ;
        RECT 2.930 287.920 1437.390 292.240 ;
      LAYER Pwell ;
        RECT 2.930 284.400 1437.390 287.920 ;
      LAYER Nwell ;
        RECT 2.930 280.080 1437.390 284.400 ;
      LAYER Pwell ;
        RECT 2.930 276.560 1437.390 280.080 ;
      LAYER Nwell ;
        RECT 2.930 272.240 1437.390 276.560 ;
      LAYER Pwell ;
        RECT 2.930 268.720 1437.390 272.240 ;
      LAYER Nwell ;
        RECT 2.930 264.400 1437.390 268.720 ;
      LAYER Pwell ;
        RECT 2.930 260.880 1437.390 264.400 ;
      LAYER Nwell ;
        RECT 2.930 256.560 1437.390 260.880 ;
      LAYER Pwell ;
        RECT 2.930 253.040 1437.390 256.560 ;
      LAYER Nwell ;
        RECT 2.930 248.720 1437.390 253.040 ;
      LAYER Pwell ;
        RECT 2.930 245.200 1437.390 248.720 ;
      LAYER Nwell ;
        RECT 2.930 240.880 1437.390 245.200 ;
      LAYER Pwell ;
        RECT 2.930 237.360 1437.390 240.880 ;
      LAYER Nwell ;
        RECT 2.930 233.040 1437.390 237.360 ;
      LAYER Pwell ;
        RECT 2.930 230.850 1437.390 233.040 ;
      LAYER Nwell ;
        RECT 2.930 3.490 1437.390 230.850 ;
      LAYER Metal1 ;
        RECT 3.360 3.620 1436.960 1144.940 ;
      LAYER Metal2 ;
        RECT 3.560 1.770 1436.260 1148.470 ;
      LAYER Metal3 ;
        RECT 3.400 1.820 1436.310 1148.420 ;
      LAYER Metal4 ;
        RECT 8.540 1147.260 32.310 1147.560 ;
        RECT 33.210 1147.260 39.590 1147.560 ;
        RECT 40.490 1147.260 46.870 1147.560 ;
        RECT 47.770 1147.260 54.150 1147.560 ;
        RECT 55.050 1147.260 61.430 1147.560 ;
        RECT 62.330 1147.260 68.710 1147.560 ;
        RECT 69.610 1147.260 75.990 1147.560 ;
        RECT 76.890 1147.260 83.270 1147.560 ;
        RECT 84.170 1147.260 90.550 1147.560 ;
        RECT 91.450 1147.260 97.830 1147.560 ;
        RECT 98.730 1147.260 105.110 1147.560 ;
        RECT 106.010 1147.260 112.390 1147.560 ;
        RECT 113.290 1147.260 119.670 1147.560 ;
        RECT 120.570 1147.260 126.950 1147.560 ;
        RECT 127.850 1147.260 134.230 1147.560 ;
        RECT 135.130 1147.260 141.510 1147.560 ;
        RECT 142.410 1147.260 148.790 1147.560 ;
        RECT 149.690 1147.260 156.070 1147.560 ;
        RECT 156.970 1147.260 163.350 1147.560 ;
        RECT 164.250 1147.260 170.630 1147.560 ;
        RECT 171.530 1147.260 177.910 1147.560 ;
        RECT 178.810 1147.260 185.190 1147.560 ;
        RECT 186.090 1147.260 192.470 1147.560 ;
        RECT 193.370 1147.260 199.750 1147.560 ;
        RECT 200.650 1147.260 207.030 1147.560 ;
        RECT 207.930 1147.260 214.310 1147.560 ;
        RECT 215.210 1147.260 221.590 1147.560 ;
        RECT 222.490 1147.260 228.870 1147.560 ;
        RECT 229.770 1147.260 236.150 1147.560 ;
        RECT 237.050 1147.260 243.430 1147.560 ;
        RECT 244.330 1147.260 250.710 1147.560 ;
        RECT 251.610 1147.260 257.990 1147.560 ;
        RECT 258.890 1147.260 265.270 1147.560 ;
        RECT 266.170 1147.260 272.550 1147.560 ;
        RECT 273.450 1147.260 279.830 1147.560 ;
        RECT 280.730 1147.260 287.110 1147.560 ;
        RECT 288.010 1147.260 294.390 1147.560 ;
        RECT 295.290 1147.260 301.670 1147.560 ;
        RECT 302.570 1147.260 308.950 1147.560 ;
        RECT 309.850 1147.260 316.230 1147.560 ;
        RECT 317.130 1147.260 323.510 1147.560 ;
        RECT 324.410 1147.260 330.790 1147.560 ;
        RECT 331.690 1147.260 338.070 1147.560 ;
        RECT 338.970 1147.260 1428.420 1147.560 ;
        RECT 8.540 1145.240 1428.420 1147.260 ;
        RECT 8.540 3.320 40.420 1145.240 ;
        RECT 44.300 3.320 77.670 1145.240 ;
        RECT 81.550 3.320 114.920 1145.240 ;
        RECT 118.800 3.320 152.170 1145.240 ;
        RECT 156.050 3.320 189.420 1145.240 ;
        RECT 193.300 3.320 226.670 1145.240 ;
        RECT 230.550 3.320 263.920 1145.240 ;
        RECT 267.800 3.320 301.170 1145.240 ;
        RECT 305.050 3.320 338.420 1145.240 ;
        RECT 342.300 3.320 375.670 1145.240 ;
        RECT 379.550 3.320 412.920 1145.240 ;
        RECT 416.800 3.320 450.170 1145.240 ;
        RECT 454.050 3.320 487.420 1145.240 ;
        RECT 491.300 3.320 524.670 1145.240 ;
        RECT 528.550 3.320 561.920 1145.240 ;
        RECT 565.800 3.320 599.170 1145.240 ;
        RECT 603.050 3.320 636.420 1145.240 ;
        RECT 640.300 3.320 673.670 1145.240 ;
        RECT 677.550 3.320 710.920 1145.240 ;
        RECT 714.800 3.320 748.170 1145.240 ;
        RECT 752.050 3.320 785.420 1145.240 ;
        RECT 789.300 3.320 822.670 1145.240 ;
        RECT 826.550 1144.940 1428.420 1145.240 ;
        RECT 826.550 3.620 859.920 1144.940 ;
        RECT 863.800 3.620 897.170 1144.940 ;
        RECT 901.050 3.620 934.420 1144.940 ;
        RECT 938.300 3.620 971.670 1144.940 ;
        RECT 975.550 3.620 1008.920 1144.940 ;
        RECT 1012.800 3.620 1046.170 1144.940 ;
        RECT 1050.050 3.620 1083.420 1144.940 ;
        RECT 1087.300 3.620 1120.670 1144.940 ;
        RECT 1124.550 3.620 1157.920 1144.940 ;
        RECT 1161.800 3.620 1195.170 1144.940 ;
        RECT 1199.050 3.620 1232.420 1144.940 ;
        RECT 1236.300 3.620 1269.670 1144.940 ;
        RECT 1273.550 3.620 1306.920 1144.940 ;
        RECT 1310.800 3.620 1344.170 1144.940 ;
        RECT 1348.050 3.620 1381.420 1144.940 ;
        RECT 1385.300 3.620 1418.670 1144.940 ;
        RECT 1422.550 3.620 1428.420 1144.940 ;
        RECT 826.550 3.320 1428.420 3.620 ;
        RECT 8.540 2.330 1428.420 3.320 ;
  END
END tt_um_MichaelBell_tinyQV
END LIBRARY

